VERSION 5.7 ;
  NOWIREEXTENSIONATPIN ON ;
  DIVIDERCHAR "/" ;
  BUSBITCHARS "[]" ;
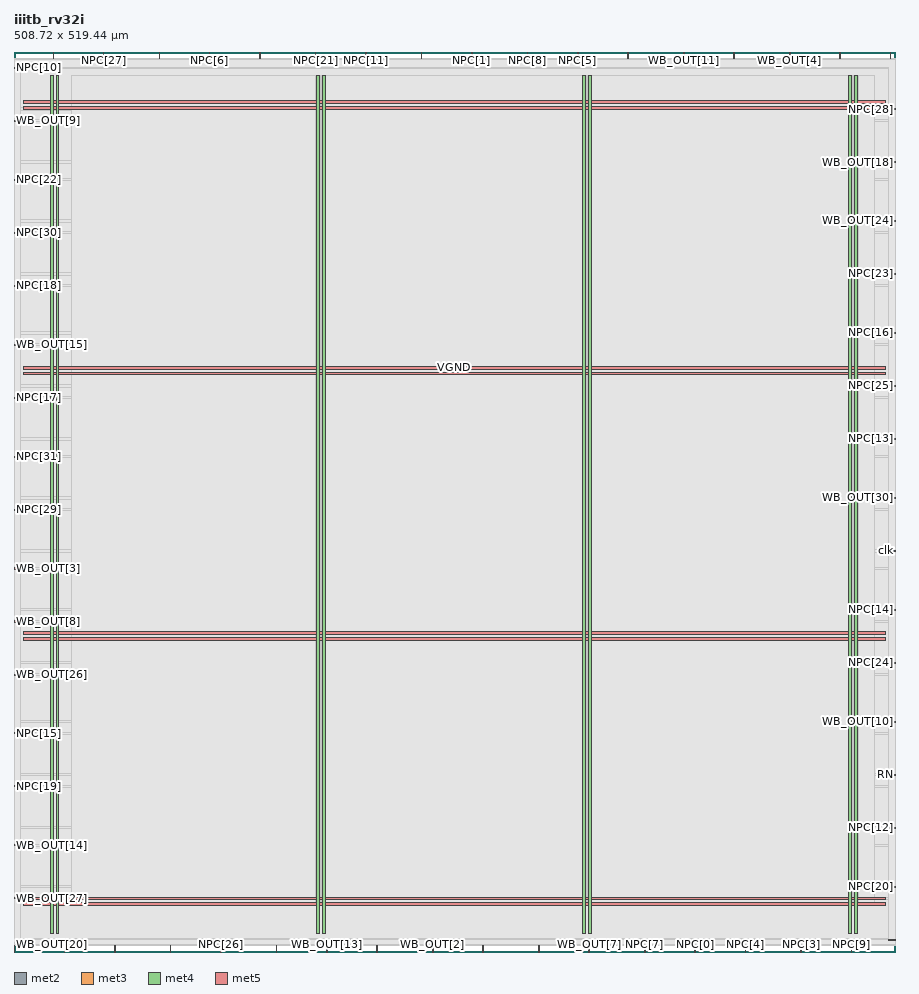
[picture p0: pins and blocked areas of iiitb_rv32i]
MACRO iiitb_rv32i
  CLASS BLOCK ;
  FOREIGN iiitb_rv32i ;
  ORIGIN 0.000 0.000 ;
  SIZE 508.720 BY 519.440 ;
  PIN NPC[0]
    DIRECTION OUTPUT TRISTATE ;
    USE SIGNAL ;
    ANTENNADIFFAREA 0.795200 ;
    PORT
      LAYER met2 ;
        RECT 392.930 0.000 393.210 4.000 ;
    END
  END NPC[0]
  PIN NPC[10]
    DIRECTION OUTPUT TRISTATE ;
    USE SIGNAL ;
    ANTENNADIFFAREA 0.795200 ;
    PORT
      LAYER met3 ;
        RECT 0.000 510.040 4.000 510.640 ;
    END
  END NPC[10]
  PIN NPC[11]
    DIRECTION OUTPUT TRISTATE ;
    USE SIGNAL ;
    ANTENNADIFFAREA 0.445500 ;
    PORT
      LAYER met2 ;
        RECT 202.950 515.440 203.230 519.440 ;
    END
  END NPC[11]
  PIN NPC[12]
    DIRECTION OUTPUT TRISTATE ;
    USE SIGNAL ;
    ANTENNADIFFAREA 0.445500 ;
    PORT
      LAYER met3 ;
        RECT 504.720 71.440 508.720 72.040 ;
    END
  END NPC[12]
  PIN NPC[13]
    DIRECTION OUTPUT TRISTATE ;
    USE SIGNAL ;
    ANTENNADIFFAREA 0.795200 ;
    PORT
      LAYER met3 ;
        RECT 504.720 295.840 508.720 296.440 ;
    END
  END NPC[13]
  PIN NPC[14]
    DIRECTION OUTPUT TRISTATE ;
    USE SIGNAL ;
    ANTENNADIFFAREA 0.795200 ;
    PORT
      LAYER met3 ;
        RECT 504.720 197.240 508.720 197.840 ;
    END
  END NPC[14]
  PIN NPC[15]
    DIRECTION OUTPUT TRISTATE ;
    USE SIGNAL ;
    ANTENNADIFFAREA 0.795200 ;
    PORT
      LAYER met3 ;
        RECT 0.000 125.840 4.000 126.440 ;
    END
  END NPC[15]
  PIN NPC[16]
    DIRECTION OUTPUT TRISTATE ;
    USE SIGNAL ;
    ANTENNADIFFAREA 0.445500 ;
    PORT
      LAYER met3 ;
        RECT 504.720 357.040 508.720 357.640 ;
    END
  END NPC[16]
  PIN NPC[17]
    DIRECTION OUTPUT TRISTATE ;
    USE SIGNAL ;
    ANTENNADIFFAREA 0.795200 ;
    PORT
      LAYER met3 ;
        RECT 0.000 319.640 4.000 320.240 ;
    END
  END NPC[17]
  PIN NPC[18]
    DIRECTION OUTPUT TRISTATE ;
    USE SIGNAL ;
    ANTENNADIFFAREA 0.795200 ;
    PORT
      LAYER met3 ;
        RECT 0.000 384.240 4.000 384.840 ;
    END
  END NPC[18]
  PIN NPC[19]
    DIRECTION OUTPUT TRISTATE ;
    USE SIGNAL ;
    ANTENNADIFFAREA 0.795200 ;
    PORT
      LAYER met3 ;
        RECT 0.000 95.240 4.000 95.840 ;
    END
  END NPC[19]
  PIN NPC[1]
    DIRECTION OUTPUT TRISTATE ;
    USE SIGNAL ;
    ANTENNADIFFAREA 0.795200 ;
    PORT
      LAYER met2 ;
        RECT 264.130 515.440 264.410 519.440 ;
    END
  END NPC[1]
  PIN NPC[20]
    DIRECTION OUTPUT TRISTATE ;
    USE SIGNAL ;
    ANTENNADIFFAREA 0.445500 ;
    PORT
      LAYER met3 ;
        RECT 504.720 37.440 508.720 38.040 ;
    END
  END NPC[20]
  PIN NPC[21]
    DIRECTION OUTPUT TRISTATE ;
    USE SIGNAL ;
    ANTENNADIFFAREA 0.795200 ;
    PORT
      LAYER met2 ;
        RECT 173.970 515.440 174.250 519.440 ;
    END
  END NPC[21]
  PIN NPC[22]
    DIRECTION OUTPUT TRISTATE ;
    USE SIGNAL ;
    ANTENNADIFFAREA 0.795200 ;
    PORT
      LAYER met3 ;
        RECT 0.000 445.440 4.000 446.040 ;
    END
  END NPC[22]
  PIN NPC[23]
    DIRECTION OUTPUT TRISTATE ;
    USE SIGNAL ;
    ANTENNADIFFAREA 0.445500 ;
    PORT
      LAYER met3 ;
        RECT 504.720 391.040 508.720 391.640 ;
    END
  END NPC[23]
  PIN NPC[24]
    DIRECTION OUTPUT TRISTATE ;
    USE SIGNAL ;
    ANTENNADIFFAREA 0.445500 ;
    PORT
      LAYER met3 ;
        RECT 504.720 166.640 508.720 167.240 ;
    END
  END NPC[24]
  PIN NPC[25]
    DIRECTION OUTPUT TRISTATE ;
    USE SIGNAL ;
    ANTENNADIFFAREA 0.445500 ;
    PORT
      LAYER met3 ;
        RECT 504.720 326.440 508.720 327.040 ;
    END
  END NPC[25]
  PIN NPC[26]
    DIRECTION OUTPUT TRISTATE ;
    USE SIGNAL ;
    ANTENNADIFFAREA 0.795200 ;
    PORT
      LAYER met2 ;
        RECT 119.230 0.000 119.510 4.000 ;
    END
  END NPC[26]
  PIN NPC[27]
    DIRECTION OUTPUT TRISTATE ;
    USE SIGNAL ;
    ANTENNADIFFAREA 0.445500 ;
    PORT
      LAYER met2 ;
        RECT 51.610 515.440 51.890 519.440 ;
    END
  END NPC[27]
  PIN NPC[28]
    DIRECTION OUTPUT TRISTATE ;
    USE SIGNAL ;
    ANTENNADIFFAREA 0.445500 ;
    PORT
      LAYER met3 ;
        RECT 504.720 486.240 508.720 486.840 ;
    END
  END NPC[28]
  PIN NPC[29]
    DIRECTION OUTPUT TRISTATE ;
    USE SIGNAL ;
    ANTENNADIFFAREA 0.795200 ;
    PORT
      LAYER met3 ;
        RECT 0.000 255.040 4.000 255.640 ;
    END
  END NPC[29]
  PIN NPC[2]
    DIRECTION OUTPUT TRISTATE ;
    USE SIGNAL ;
    ANTENNADIFFAREA 0.795200 ;
    PORT
      LAYER met2 ;
        RECT 29.070 0.000 29.350 4.000 ;
    END
  END NPC[2]
  PIN NPC[30]
    DIRECTION OUTPUT TRISTATE ;
    USE SIGNAL ;
    ANTENNADIFFAREA 0.795200 ;
    PORT
      LAYER met3 ;
        RECT 0.000 414.840 4.000 415.440 ;
    END
  END NPC[30]
  PIN NPC[31]
    DIRECTION OUTPUT TRISTATE ;
    USE SIGNAL ;
    ANTENNADIFFAREA 0.795200 ;
    PORT
      LAYER met3 ;
        RECT 0.000 285.640 4.000 286.240 ;
    END
  END NPC[31]
  PIN NPC[3]
    DIRECTION OUTPUT TRISTATE ;
    USE SIGNAL ;
    ANTENNADIFFAREA 0.795200 ;
    PORT
      LAYER met2 ;
        RECT 454.110 0.000 454.390 4.000 ;
    END
  END NPC[3]
  PIN NPC[4]
    DIRECTION OUTPUT TRISTATE ;
    USE SIGNAL ;
    ANTENNADIFFAREA 0.795200 ;
    PORT
      LAYER met2 ;
        RECT 421.910 0.000 422.190 4.000 ;
    END
  END NPC[4]
  PIN NPC[5]
    DIRECTION OUTPUT TRISTATE ;
    USE SIGNAL ;
    ANTENNADIFFAREA 0.795200 ;
    PORT
      LAYER met2 ;
        RECT 325.310 515.440 325.590 519.440 ;
    END
  END NPC[5]
  PIN NPC[6]
    DIRECTION OUTPUT TRISTATE ;
    USE SIGNAL ;
    ANTENNADIFFAREA 0.445500 ;
    PORT
      LAYER met2 ;
        RECT 112.790 515.440 113.070 519.440 ;
    END
  END NPC[6]
  PIN NPC[7]
    DIRECTION OUTPUT TRISTATE ;
    USE SIGNAL ;
    ANTENNADIFFAREA 0.795200 ;
    PORT
      LAYER met2 ;
        RECT 363.950 0.000 364.230 4.000 ;
    END
  END NPC[7]
  PIN NPC[8]
    DIRECTION OUTPUT TRISTATE ;
    USE SIGNAL ;
    ANTENNADIFFAREA 0.795200 ;
    PORT
      LAYER met2 ;
        RECT 296.330 515.440 296.610 519.440 ;
    END
  END NPC[8]
  PIN NPC[9]
    DIRECTION OUTPUT TRISTATE ;
    USE SIGNAL ;
    ANTENNADIFFAREA 0.795200 ;
    PORT
      LAYER met2 ;
        RECT 483.090 0.000 483.370 4.000 ;
    END
  END NPC[9]
  PIN RN
    DIRECTION INPUT ;
    USE SIGNAL ;
    ANTENNAGATEAREA 0.159000 ;
    PORT
      LAYER met3 ;
        RECT 504.720 102.040 508.720 102.640 ;
    END
  END RN
  PIN VGND
    DIRECTION INOUT ;
    USE GROUND ;
    PORT
      LAYER met4 ;
        RECT 24.340 10.640 25.940 506.160 ;
    END
    PORT
      LAYER met4 ;
        RECT 177.940 10.640 179.540 506.160 ;
    END
    PORT
      LAYER met4 ;
        RECT 331.540 10.640 333.140 506.160 ;
    END
    PORT
      LAYER met4 ;
        RECT 485.140 10.640 486.740 506.160 ;
    END
    PORT
      LAYER met5 ;
        RECT 5.280 30.030 503.020 31.630 ;
    END
    PORT
      LAYER met5 ;
        RECT 5.280 183.210 503.020 184.810 ;
    END
    PORT
      LAYER met5 ;
        RECT 5.280 336.390 503.020 337.990 ;
    END
    PORT
      LAYER met5 ;
        RECT 5.280 489.570 503.020 491.170 ;
    END
  END VGND
  PIN VPWR
    DIRECTION INOUT ;
    USE POWER ;
    PORT
      LAYER met4 ;
        RECT 21.040 10.640 22.640 506.160 ;
    END
    PORT
      LAYER met4 ;
        RECT 174.640 10.640 176.240 506.160 ;
    END
    PORT
      LAYER met4 ;
        RECT 328.240 10.640 329.840 506.160 ;
    END
    PORT
      LAYER met4 ;
        RECT 481.840 10.640 483.440 506.160 ;
    END
    PORT
      LAYER met5 ;
        RECT 5.280 26.730 503.020 28.330 ;
    END
    PORT
      LAYER met5 ;
        RECT 5.280 179.910 503.020 181.510 ;
    END
    PORT
      LAYER met5 ;
        RECT 5.280 333.090 503.020 334.690 ;
    END
    PORT
      LAYER met5 ;
        RECT 5.280 486.270 503.020 487.870 ;
    END
  END VPWR
  PIN WB_OUT[0]
    DIRECTION OUTPUT TRISTATE ;
    USE SIGNAL ;
    ANTENNADIFFAREA 0.795200 ;
    PORT
      LAYER met2 ;
        RECT 302.770 0.000 303.050 4.000 ;
    END
  END WB_OUT[0]
  PIN WB_OUT[10]
    DIRECTION OUTPUT TRISTATE ;
    USE SIGNAL ;
    ANTENNADIFFAREA 0.445500 ;
    PORT
      LAYER met3 ;
        RECT 504.720 132.640 508.720 133.240 ;
    END
  END WB_OUT[10]
  PIN WB_OUT[11]
    DIRECTION OUTPUT TRISTATE ;
    USE SIGNAL ;
    ANTENNADIFFAREA 0.795200 ;
    PORT
      LAYER met2 ;
        RECT 386.490 515.440 386.770 519.440 ;
    END
  END WB_OUT[11]
  PIN WB_OUT[12]
    DIRECTION OUTPUT TRISTATE ;
    USE SIGNAL ;
    ANTENNADIFFAREA 0.795200 ;
    PORT
      LAYER met2 ;
        RECT 415.470 515.440 415.750 519.440 ;
    END
  END WB_OUT[12]
  PIN WB_OUT[13]
    DIRECTION OUTPUT TRISTATE ;
    USE SIGNAL ;
    ANTENNADIFFAREA 0.795200 ;
    PORT
      LAYER met2 ;
        RECT 180.410 0.000 180.690 4.000 ;
    END
  END WB_OUT[13]
  PIN WB_OUT[14]
    DIRECTION OUTPUT TRISTATE ;
    USE SIGNAL ;
    ANTENNADIFFAREA 0.795200 ;
    PORT
      LAYER met3 ;
        RECT 0.000 61.240 4.000 61.840 ;
    END
  END WB_OUT[14]
  PIN WB_OUT[15]
    DIRECTION OUTPUT TRISTATE ;
    USE SIGNAL ;
    ANTENNADIFFAREA 0.795200 ;
    PORT
      LAYER met3 ;
        RECT 0.000 350.240 4.000 350.840 ;
    END
  END WB_OUT[15]
  PIN WB_OUT[16]
    DIRECTION OUTPUT TRISTATE ;
    USE SIGNAL ;
    ANTENNADIFFAREA 0.445500 ;
    PORT
      LAYER met2 ;
        RECT 354.290 515.440 354.570 519.440 ;
    END
  END WB_OUT[16]
  PIN WB_OUT[17]
    DIRECTION OUTPUT TRISTATE ;
    USE SIGNAL ;
    ANTENNADIFFAREA 0.795200 ;
    PORT
      LAYER met2 ;
        RECT 476.650 515.440 476.930 519.440 ;
    END
  END WB_OUT[17]
  PIN WB_OUT[18]
    DIRECTION OUTPUT TRISTATE ;
    USE SIGNAL ;
    ANTENNADIFFAREA 0.445500 ;
    PORT
      LAYER met3 ;
        RECT 504.720 455.640 508.720 456.240 ;
    END
  END WB_OUT[18]
  PIN WB_OUT[19]
    DIRECTION OUTPUT TRISTATE ;
    USE SIGNAL ;
    ANTENNADIFFAREA 0.795200 ;
    PORT
      LAYER met2 ;
        RECT 235.150 515.440 235.430 519.440 ;
    END
  END WB_OUT[19]
  PIN WB_OUT[1]
    DIRECTION OUTPUT TRISTATE ;
    USE SIGNAL ;
    ANTENNADIFFAREA 0.795200 ;
    PORT
      LAYER met2 ;
        RECT 58.050 0.000 58.330 4.000 ;
    END
  END WB_OUT[1]
  PIN WB_OUT[20]
    DIRECTION OUTPUT TRISTATE ;
    USE SIGNAL ;
    ANTENNADIFFAREA 0.795200 ;
    PORT
      LAYER met2 ;
        RECT 0.090 0.000 0.370 4.000 ;
    END
  END WB_OUT[20]
  PIN WB_OUT[21]
    DIRECTION OUTPUT TRISTATE ;
    USE SIGNAL ;
    ANTENNADIFFAREA 0.795200 ;
    PORT
      LAYER met2 ;
        RECT 22.630 515.440 22.910 519.440 ;
    END
  END WB_OUT[21]
  PIN WB_OUT[22]
    DIRECTION OUTPUT TRISTATE ;
    USE SIGNAL ;
    ANTENNADIFFAREA 0.795200 ;
    PORT
      LAYER met2 ;
        RECT 505.630 515.440 505.910 519.440 ;
    END
  END WB_OUT[22]
  PIN WB_OUT[23]
    DIRECTION OUTPUT TRISTATE ;
    USE SIGNAL ;
    ANTENNADIFFAREA 0.795200 ;
    PORT
      LAYER met2 ;
        RECT 209.390 0.000 209.670 4.000 ;
    END
  END WB_OUT[23]
  PIN WB_OUT[24]
    DIRECTION OUTPUT TRISTATE ;
    USE SIGNAL ;
    ANTENNADIFFAREA 0.445500 ;
    PORT
      LAYER met3 ;
        RECT 504.720 421.640 508.720 422.240 ;
    END
  END WB_OUT[24]
  PIN WB_OUT[25]
    DIRECTION OUTPUT TRISTATE ;
    USE SIGNAL ;
    ANTENNADIFFAREA 0.445500 ;
    PORT
      LAYER met3 ;
        RECT 504.720 6.840 508.720 7.440 ;
    END
  END WB_OUT[25]
  PIN WB_OUT[26]
    DIRECTION OUTPUT TRISTATE ;
    USE SIGNAL ;
    ANTENNADIFFAREA 0.795200 ;
    PORT
      LAYER met3 ;
        RECT 0.000 159.840 4.000 160.440 ;
    END
  END WB_OUT[26]
  PIN WB_OUT[27]
    DIRECTION OUTPUT TRISTATE ;
    USE SIGNAL ;
    ANTENNADIFFAREA 0.795200 ;
    PORT
      LAYER met3 ;
        RECT 0.000 30.640 4.000 31.240 ;
    END
  END WB_OUT[27]
  PIN WB_OUT[28]
    DIRECTION OUTPUT TRISTATE ;
    USE SIGNAL ;
    ANTENNADIFFAREA 0.795200 ;
    PORT
      LAYER met2 ;
        RECT 90.250 0.000 90.530 4.000 ;
    END
  END WB_OUT[28]
  PIN WB_OUT[29]
    DIRECTION OUTPUT TRISTATE ;
    USE SIGNAL ;
    ANTENNADIFFAREA 0.795200 ;
    PORT
      LAYER met2 ;
        RECT 151.430 0.000 151.710 4.000 ;
    END
  END WB_OUT[29]
  PIN WB_OUT[2]
    DIRECTION OUTPUT TRISTATE ;
    USE SIGNAL ;
    ANTENNADIFFAREA 0.795200 ;
    PORT
      LAYER met2 ;
        RECT 241.590 0.000 241.870 4.000 ;
    END
  END WB_OUT[2]
  PIN WB_OUT[30]
    DIRECTION OUTPUT TRISTATE ;
    USE SIGNAL ;
    ANTENNADIFFAREA 0.795200 ;
    PORT
      LAYER met3 ;
        RECT 504.720 261.840 508.720 262.440 ;
    END
  END WB_OUT[30]
  PIN WB_OUT[31]
    DIRECTION OUTPUT TRISTATE ;
    USE SIGNAL ;
    ANTENNADIFFAREA 0.795200 ;
    PORT
      LAYER met2 ;
        RECT 270.570 0.000 270.850 4.000 ;
    END
  END WB_OUT[31]
  PIN WB_OUT[3]
    DIRECTION OUTPUT TRISTATE ;
    USE SIGNAL ;
    ANTENNADIFFAREA 0.795200 ;
    PORT
      LAYER met3 ;
        RECT 0.000 221.040 4.000 221.640 ;
    END
  END WB_OUT[3]
  PIN WB_OUT[4]
    DIRECTION OUTPUT TRISTATE ;
    USE SIGNAL ;
    ANTENNADIFFAREA 0.795200 ;
    PORT
      LAYER met2 ;
        RECT 447.670 515.440 447.950 519.440 ;
    END
  END WB_OUT[4]
  PIN WB_OUT[5]
    DIRECTION OUTPUT TRISTATE ;
    USE SIGNAL ;
    ANTENNADIFFAREA 0.795200 ;
    PORT
      LAYER met2 ;
        RECT 83.810 515.440 84.090 519.440 ;
    END
  END WB_OUT[5]
  PIN WB_OUT[6]
    DIRECTION OUTPUT TRISTATE ;
    USE SIGNAL ;
    ANTENNADIFFAREA 0.795200 ;
    PORT
      LAYER met2 ;
        RECT 141.770 515.440 142.050 519.440 ;
    END
  END WB_OUT[6]
  PIN WB_OUT[7]
    DIRECTION OUTPUT TRISTATE ;
    USE SIGNAL ;
    ANTENNADIFFAREA 0.795200 ;
    PORT
      LAYER met2 ;
        RECT 331.750 0.000 332.030 4.000 ;
    END
  END WB_OUT[7]
  PIN WB_OUT[8]
    DIRECTION OUTPUT TRISTATE ;
    USE SIGNAL ;
    ANTENNADIFFAREA 0.795200 ;
    PORT
      LAYER met3 ;
        RECT 0.000 190.440 4.000 191.040 ;
    END
  END WB_OUT[8]
  PIN WB_OUT[9]
    DIRECTION OUTPUT TRISTATE ;
    USE SIGNAL ;
    ANTENNADIFFAREA 0.795200 ;
    PORT
      LAYER met3 ;
        RECT 0.000 479.440 4.000 480.040 ;
    END
  END WB_OUT[9]
  PIN clk
    DIRECTION INPUT ;
    USE SIGNAL ;
    ANTENNAGATEAREA 0.852000 ;
    PORT
      LAYER met3 ;
        RECT 504.720 231.240 508.720 231.840 ;
    END
  END clk
  OBS
      LAYER li1 ;
        RECT 5.520 10.795 502.780 506.005 ;
      LAYER met1 ;
        RECT 0.070 9.900 508.690 506.160 ;
      LAYER met2 ;
        RECT 0.100 515.160 22.350 515.440 ;
        RECT 23.190 515.160 51.330 515.440 ;
        RECT 52.170 515.160 83.530 515.440 ;
        RECT 84.370 515.160 112.510 515.440 ;
        RECT 113.350 515.160 141.490 515.440 ;
        RECT 142.330 515.160 173.690 515.440 ;
        RECT 174.530 515.160 202.670 515.440 ;
        RECT 203.510 515.160 234.870 515.440 ;
        RECT 235.710 515.160 263.850 515.440 ;
        RECT 264.690 515.160 296.050 515.440 ;
        RECT 296.890 515.160 325.030 515.440 ;
        RECT 325.870 515.160 354.010 515.440 ;
        RECT 354.850 515.160 386.210 515.440 ;
        RECT 387.050 515.160 415.190 515.440 ;
        RECT 416.030 515.160 447.390 515.440 ;
        RECT 448.230 515.160 476.370 515.440 ;
        RECT 477.210 515.160 505.350 515.440 ;
        RECT 506.190 515.160 508.660 515.440 ;
        RECT 0.100 4.280 508.660 515.160 ;
        RECT 0.650 3.670 28.790 4.280 ;
        RECT 29.630 3.670 57.770 4.280 ;
        RECT 58.610 3.670 89.970 4.280 ;
        RECT 90.810 3.670 118.950 4.280 ;
        RECT 119.790 3.670 151.150 4.280 ;
        RECT 151.990 3.670 180.130 4.280 ;
        RECT 180.970 3.670 209.110 4.280 ;
        RECT 209.950 3.670 241.310 4.280 ;
        RECT 242.150 3.670 270.290 4.280 ;
        RECT 271.130 3.670 302.490 4.280 ;
        RECT 303.330 3.670 331.470 4.280 ;
        RECT 332.310 3.670 363.670 4.280 ;
        RECT 364.510 3.670 392.650 4.280 ;
        RECT 393.490 3.670 421.630 4.280 ;
        RECT 422.470 3.670 453.830 4.280 ;
        RECT 454.670 3.670 482.810 4.280 ;
        RECT 483.650 3.670 508.660 4.280 ;
      LAYER met3 ;
        RECT 4.400 509.640 504.720 510.505 ;
        RECT 3.990 487.240 504.720 509.640 ;
        RECT 3.990 485.840 504.320 487.240 ;
        RECT 3.990 480.440 504.720 485.840 ;
        RECT 4.400 479.040 504.720 480.440 ;
        RECT 3.990 456.640 504.720 479.040 ;
        RECT 3.990 455.240 504.320 456.640 ;
        RECT 3.990 446.440 504.720 455.240 ;
        RECT 4.400 445.040 504.720 446.440 ;
        RECT 3.990 422.640 504.720 445.040 ;
        RECT 3.990 421.240 504.320 422.640 ;
        RECT 3.990 415.840 504.720 421.240 ;
        RECT 4.400 414.440 504.720 415.840 ;
        RECT 3.990 392.040 504.720 414.440 ;
        RECT 3.990 390.640 504.320 392.040 ;
        RECT 3.990 385.240 504.720 390.640 ;
        RECT 4.400 383.840 504.720 385.240 ;
        RECT 3.990 358.040 504.720 383.840 ;
        RECT 3.990 356.640 504.320 358.040 ;
        RECT 3.990 351.240 504.720 356.640 ;
        RECT 4.400 349.840 504.720 351.240 ;
        RECT 3.990 327.440 504.720 349.840 ;
        RECT 3.990 326.040 504.320 327.440 ;
        RECT 3.990 320.640 504.720 326.040 ;
        RECT 4.400 319.240 504.720 320.640 ;
        RECT 3.990 296.840 504.720 319.240 ;
        RECT 3.990 295.440 504.320 296.840 ;
        RECT 3.990 286.640 504.720 295.440 ;
        RECT 4.400 285.240 504.720 286.640 ;
        RECT 3.990 262.840 504.720 285.240 ;
        RECT 3.990 261.440 504.320 262.840 ;
        RECT 3.990 256.040 504.720 261.440 ;
        RECT 4.400 254.640 504.720 256.040 ;
        RECT 3.990 232.240 504.720 254.640 ;
        RECT 3.990 230.840 504.320 232.240 ;
        RECT 3.990 222.040 504.720 230.840 ;
        RECT 4.400 220.640 504.720 222.040 ;
        RECT 3.990 198.240 504.720 220.640 ;
        RECT 3.990 196.840 504.320 198.240 ;
        RECT 3.990 191.440 504.720 196.840 ;
        RECT 4.400 190.040 504.720 191.440 ;
        RECT 3.990 167.640 504.720 190.040 ;
        RECT 3.990 166.240 504.320 167.640 ;
        RECT 3.990 160.840 504.720 166.240 ;
        RECT 4.400 159.440 504.720 160.840 ;
        RECT 3.990 133.640 504.720 159.440 ;
        RECT 3.990 132.240 504.320 133.640 ;
        RECT 3.990 126.840 504.720 132.240 ;
        RECT 4.400 125.440 504.720 126.840 ;
        RECT 3.990 103.040 504.720 125.440 ;
        RECT 3.990 101.640 504.320 103.040 ;
        RECT 3.990 96.240 504.720 101.640 ;
        RECT 4.400 94.840 504.720 96.240 ;
        RECT 3.990 72.440 504.720 94.840 ;
        RECT 3.990 71.040 504.320 72.440 ;
        RECT 3.990 62.240 504.720 71.040 ;
        RECT 4.400 60.840 504.720 62.240 ;
        RECT 3.990 38.440 504.720 60.840 ;
        RECT 3.990 37.040 504.320 38.440 ;
        RECT 3.990 31.640 504.720 37.040 ;
        RECT 4.400 30.240 504.720 31.640 ;
        RECT 3.990 7.840 504.720 30.240 ;
        RECT 3.990 6.975 504.320 7.840 ;
      LAYER met4 ;
        RECT 33.415 27.375 174.240 505.745 ;
        RECT 176.640 27.375 177.540 505.745 ;
        RECT 179.940 27.375 327.840 505.745 ;
        RECT 330.240 27.375 331.140 505.745 ;
        RECT 333.540 27.375 481.440 505.745 ;
        RECT 483.840 27.375 484.740 505.745 ;
        RECT 487.140 27.375 496.505 505.745 ;
  END
END iiitb_rv32i
END LIBRARY

